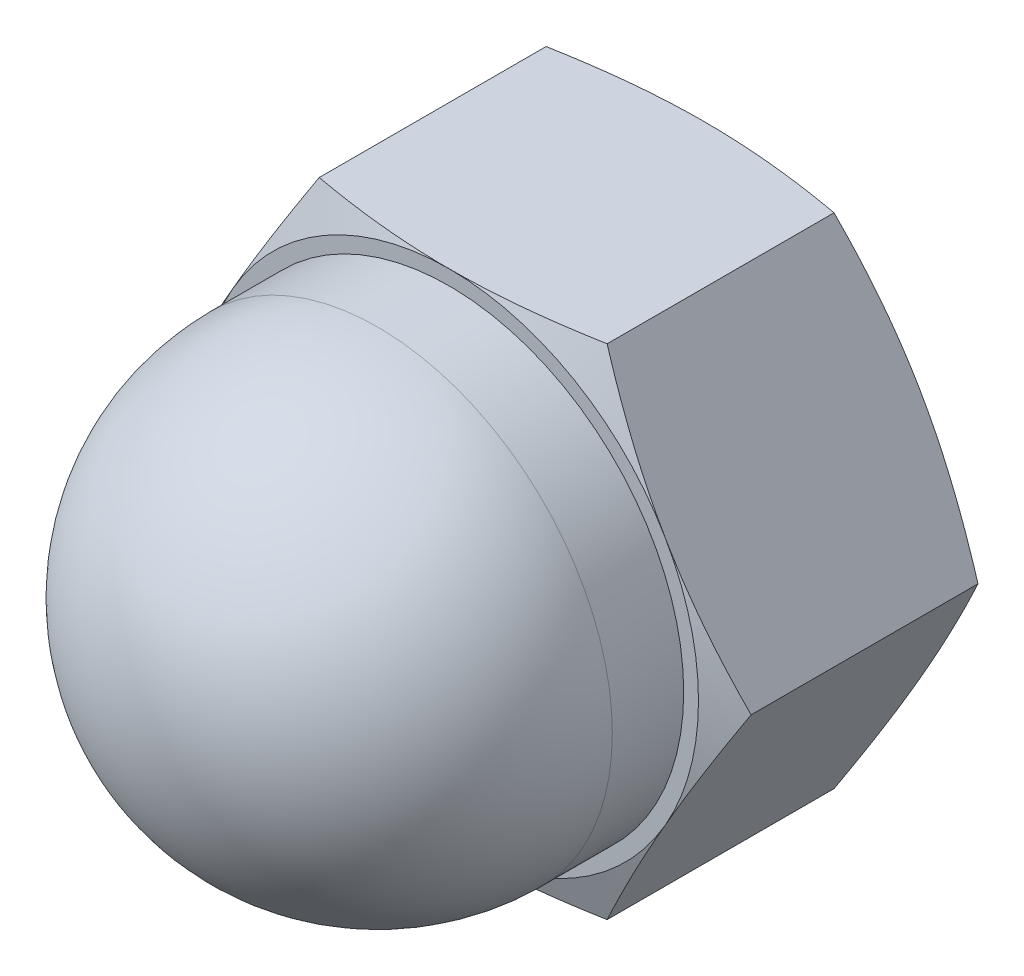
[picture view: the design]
ISO-10303-21;
HEADER;
FILE_DESCRIPTION(('STEP AP214'),'2;1');
FILE_NAME('part.step','',(''),(''),'','','');
FILE_SCHEMA(('AUTOMOTIVE_DESIGN { 1 0 10303 214 1 1 1 1 }'));
ENDSEC;
DATA;
#1=APPLICATION_CONTEXT('core data for automotive mechanical design processes');
#2=APPLICATION_PROTOCOL_DEFINITION('international standard','automotive_design',2000,#1);
#3=PRODUCT_CONTEXT('',#1,'mechanical');
#4=PRODUCT('Part','Part','',(#3));
#5=PRODUCT_RELATED_PRODUCT_CATEGORY('part','',(#4));
#6=PRODUCT_DEFINITION_FORMATION('','',#4);
#7=PRODUCT_DEFINITION_CONTEXT('part definition',#1,'design');
#8=PRODUCT_DEFINITION('design','',#6,#7);
#9=PRODUCT_DEFINITION_SHAPE('','',#8);
#10=(LENGTH_UNIT() NAMED_UNIT(*) SI_UNIT(.MILLI.,.METRE.));
#11=(NAMED_UNIT(*) PLANE_ANGLE_UNIT() SI_UNIT($,.RADIAN.));
#12=(NAMED_UNIT(*) SI_UNIT($,.STERADIAN.) SOLID_ANGLE_UNIT());
#13=UNCERTAINTY_MEASURE_WITH_UNIT(LENGTH_MEASURE(1.E-05),#10,'distance_accuracy_value','');
#14=(GEOMETRIC_REPRESENTATION_CONTEXT(3) GLOBAL_UNCERTAINTY_ASSIGNED_CONTEXT((#13)) GLOBAL_UNIT_ASSIGNED_CONTEXT((#10,
#11,#12)) REPRESENTATION_CONTEXT('',''));
#15=CARTESIAN_POINT('',(0.,0.,0.));
#16=DIRECTION('',(0.,0.,1.));
#17=DIRECTION('',(1.,0.,0.));
#18=AXIS2_PLACEMENT_3D('',#15,#16,#17);
#19=CARTESIAN_POINT('',(2.82324281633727,-4.89,0.));
#20=DIRECTION('',(0.,0.,-1.));
#21=DIRECTION('',(-1.,0.,0.));
#22=AXIS2_PLACEMENT_3D('',#19,#20,#21);
#23=PLANE('',#22);
#24=CARTESIAN_POINT('',(0.,0.,0.));
#25=DIRECTION('',(0.,0.,1.));
#26=DIRECTION('',(1.,0.,0.));
#27=AXIS2_PLACEMENT_3D('',#24,#25,#26);
#28=CIRCLE('',#27,4.6);
#29=CARTESIAN_POINT('',(4.6,0.,0.));
#30=VERTEX_POINT('',#29);
#31=EDGE_CURVE('E152',#30,#30,#28,.T.);
#32=ORIENTED_EDGE('',*,*,#31,.F.);
#33=EDGE_LOOP('',(#32));
#34=FACE_BOUND('',#33,.T.);
#35=CARTESIAN_POINT('',(0.,0.,0.));
#36=DIRECTION('',(0.,0.,-1.));
#37=DIRECTION('',(-1.,0.,0.));
#38=AXIS2_PLACEMENT_3D('',#35,#36,#37);
#39=CIRCLE('',#38,4.89);
#40=CARTESIAN_POINT('',(-4.2348642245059,2.445,0.));
#41=VERTEX_POINT('',#40);
#42=CARTESIAN_POINT('',(-4.2348642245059,-2.445,0.));
#43=VERTEX_POINT('',#42);
#44=EDGE_CURVE('E307',#41,#43,#39,.F.);
#45=ORIENTED_EDGE('',*,*,#44,.T.);
#46=CARTESIAN_POINT('',(0.,-4.89,0.));
#47=VERTEX_POINT('',#46);
#48=EDGE_CURVE('E62',#43,#47,#39,.F.);
#49=ORIENTED_EDGE('',*,*,#48,.T.);
#50=CARTESIAN_POINT('',(4.2348642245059,-2.445,0.));
#51=VERTEX_POINT('',#50);
#52=EDGE_CURVE('E313',#47,#51,#39,.F.);
#53=ORIENTED_EDGE('',*,*,#52,.T.);
#54=CARTESIAN_POINT('',(4.2348642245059,2.445,0.));
#55=VERTEX_POINT('',#54);
#56=EDGE_CURVE('E70',#51,#55,#39,.F.);
#57=ORIENTED_EDGE('',*,*,#56,.T.);
#58=CARTESIAN_POINT('',(0.,4.89,0.));
#59=VERTEX_POINT('',#58);
#60=EDGE_CURVE('E309',#55,#59,#39,.F.);
#61=ORIENTED_EDGE('',*,*,#60,.T.);
#62=CARTESIAN_POINT('',(0.,0.,0.));
#63=DIRECTION('',(0.,0.,-1.));
#64=DIRECTION('',(-1.,0.,0.));
#65=AXIS2_PLACEMENT_3D('',#62,#63,#64);
#66=CIRCLE('',#65,4.89);
#67=EDGE_CURVE('E160',#41,#59,#66,.T.);
#68=ORIENTED_EDGE('',*,*,#67,.F.);
#69=EDGE_LOOP('',(#45,#49,#53,#57,#61,#68));
#70=FACE_BOUND('',#69,.T.);
#71=ADVANCED_FACE('F47',(#34,#70),#23,.F.);
#72=CARTESIAN_POINT('',(2.82324281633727,-4.89,-5.));
#73=DIRECTION('',(0.866025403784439,-0.5,0.));
#74=DIRECTION('',(0.5,0.866025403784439,0.));
#75=AXIS2_PLACEMENT_3D('',#72,#73,#74);
#76=PLANE('',#75);
#77=CARTESIAN_POINT('',(2.82312734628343,-4.8902,-0.275380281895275));
#78=CARTESIAN_POINT('',(2.94005354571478,-4.68767788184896,-0.232806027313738));
#79=CARTESIAN_POINT('',(3.05736532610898,-4.48448791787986,-0.194077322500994));
#80=CARTESIAN_POINT('',(3.29275168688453,-4.07678678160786,-0.125940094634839));
#81=CARTESIAN_POINT('',(3.4108267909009,-3.87227470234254,-0.0965388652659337));
#82=CARTESIAN_POINT('',(3.64642938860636,-3.46419903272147,-0.04898319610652));
#83=CARTESIAN_POINT('',(3.7639515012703,-3.26064476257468,-0.0307250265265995));
#84=CARTESIAN_POINT('',(3.9992705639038,-2.85306019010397,-0.00623568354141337));
#85=CARTESIAN_POINT('',(4.11706739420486,-2.64903009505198,0.));
#86=CARTESIAN_POINT('',(4.35266105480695,-2.24096990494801,0.));
#87=CARTESIAN_POINT('',(4.470457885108,-2.03693980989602,-0.00623568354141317));
#88=CARTESIAN_POINT('',(4.7057769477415,-1.62935523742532,-0.0307250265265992));
#89=CARTESIAN_POINT('',(4.82329906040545,-1.42580096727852,-0.0489831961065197));
#90=CARTESIAN_POINT('',(5.05890165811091,-1.01772529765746,-0.0965388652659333));
#91=CARTESIAN_POINT('',(5.17697676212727,-0.813213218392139,-0.125940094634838));
#92=CARTESIAN_POINT('',(5.41236312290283,-0.40551208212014,-0.194077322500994));
#93=CARTESIAN_POINT('',(5.52967490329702,-0.202322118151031,-0.232806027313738));
#94=CARTESIAN_POINT('',(5.64660110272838,0.000200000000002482,-0.275380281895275));
#95=B_SPLINE_CURVE_WITH_KNOTS('',3,(#77,#78,#79,#80,#81,#82,#83,#84,#85,#86,#87,#88,#89,#90,#91,
#92,#93,#94),.UNSPECIFIED.,.F.,.F.,(4,2,2,2,2,2,2,2,4),(0.,0.713162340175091,1.42688097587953,
2.13385008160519,2.84055392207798,3.54725776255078,4.25422686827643,4.96794550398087,
5.68110784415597),.UNSPECIFIED.);
#96=CARTESIAN_POINT('',(2.82324281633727,-4.89,-0.275338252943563));
#97=VERTEX_POINT('',#96);
#98=EDGE_CURVE('E275',#97,#51,#95,.T.);
#99=ORIENTED_EDGE('',*,*,#98,.F.);
#100=DIRECTION('',(0.,0.,1.));
#101=VECTOR('',#100,1.);
#102=CARTESIAN_POINT('',(2.82324281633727,-4.89,-5.));
#103=LINE('',#102,#101);
#104=CARTESIAN_POINT('',(2.82324281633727,-4.89,-4.72466174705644));
#105=VERTEX_POINT('',#104);
#106=EDGE_CURVE('E278',#105,#97,#103,.T.);
#107=ORIENTED_EDGE('',*,*,#106,.F.);
#108=CARTESIAN_POINT('',(5.64660110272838,0.000200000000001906,-4.72461971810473));
#109=CARTESIAN_POINT('',(5.52967490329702,-0.202322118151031,-4.76719397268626));
#110=CARTESIAN_POINT('',(5.41236312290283,-0.405512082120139,-4.80592267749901));
#111=CARTESIAN_POINT('',(5.17697676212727,-0.813213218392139,-4.87405990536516));
#112=CARTESIAN_POINT('',(5.05890165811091,-1.01772529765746,-4.90346113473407));
#113=CARTESIAN_POINT('',(4.82329906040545,-1.42580096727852,-4.95101680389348));
#114=CARTESIAN_POINT('',(4.7057769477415,-1.62935523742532,-4.9692749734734));
#115=CARTESIAN_POINT('',(4.470457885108,-2.03693980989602,-4.99376431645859));
#116=CARTESIAN_POINT('',(4.35266105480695,-2.24096990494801,-5.));
#117=CARTESIAN_POINT('',(4.11706739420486,-2.64903009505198,-5.));
#118=CARTESIAN_POINT('',(3.99927056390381,-2.85306019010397,-4.99376431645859));
#119=CARTESIAN_POINT('',(3.76395150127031,-3.26064476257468,-4.9692749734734));
#120=CARTESIAN_POINT('',(3.64642938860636,-3.46419903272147,-4.95101680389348));
#121=CARTESIAN_POINT('',(3.4108267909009,-3.87227470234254,-4.90346113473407));
#122=CARTESIAN_POINT('',(3.29275168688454,-4.07678678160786,-4.87405990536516));
#123=CARTESIAN_POINT('',(3.05736532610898,-4.48448791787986,-4.80592267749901));
#124=CARTESIAN_POINT('',(2.94005354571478,-4.68767788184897,-4.76719397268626));
#125=CARTESIAN_POINT('',(2.82312734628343,-4.8902,-4.72461971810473));
#126=B_SPLINE_CURVE_WITH_KNOTS('',3,(#108,#109,#110,#111,#112,#113,#114,#115,#116,#117,#118,
#119,#120,#121,#122,#123,#124,#125),.UNSPECIFIED.,.F.,.F.,(4,2,2,2,2,2,2,2,4),(0.,
0.713162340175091,1.42688097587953,2.13385008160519,2.84055392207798,3.54725776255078,
4.25422686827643,4.96794550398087,5.68110784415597),.UNSPECIFIED.);
#127=CARTESIAN_POINT('',(4.2348642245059,-2.445,-5.));
#128=VERTEX_POINT('',#127);
#129=EDGE_CURVE('E255',#128,#105,#126,.T.);
#130=ORIENTED_EDGE('',*,*,#129,.F.);
#131=CARTESIAN_POINT('',(5.64648563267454,0.,-4.72466174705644));
#132=VERTEX_POINT('',#131);
#133=EDGE_CURVE('E261',#132,#128,#126,.T.);
#134=ORIENTED_EDGE('',*,*,#133,.F.);
#135=DIRECTION('',(0.,0.,1.));
#136=VECTOR('',#135,1.);
#137=CARTESIAN_POINT('',(5.64648563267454,0.,-5.));
#138=LINE('',#137,#136);
#139=CARTESIAN_POINT('',(5.64648563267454,0.,-0.275338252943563));
#140=VERTEX_POINT('',#139);
#141=EDGE_CURVE('E305',#132,#140,#138,.T.);
#142=ORIENTED_EDGE('',*,*,#141,.T.);
#143=EDGE_CURVE('E201',#51,#140,#95,.T.);
#144=ORIENTED_EDGE('',*,*,#143,.F.);
#145=EDGE_LOOP('',(#99,#107,#130,#134,#142,#144));
#146=FACE_BOUND('',#145,.T.);
#147=ADVANCED_FACE('F233',(#146),#76,.T.);
#148=CARTESIAN_POINT('',(-2.82324281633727,-4.89,-5.));
#149=DIRECTION('',(0.,-1.,0.));
#150=DIRECTION('',(0.,0.,-1.));
#151=AXIS2_PLACEMENT_3D('',#148,#149,#150);
#152=PLANE('',#151);
#153=CARTESIAN_POINT('',(-7.47495425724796,-4.89,-1.47129843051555));
#154=CARTESIAN_POINT('',(-7.25371297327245,-4.89,-1.40393054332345));
#155=CARTESIAN_POINT('',(-7.03222787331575,-4.89,-1.33734875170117));
#156=CARTESIAN_POINT('',(-6.5886459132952,-4.89,-1.20619222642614));
#157=CARTESIAN_POINT('',(-6.36654900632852,-4.89,-1.14161765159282));
#158=CARTESIAN_POINT('',(-5.92123916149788,-4.89,-1.01480300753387));
#159=CARTESIAN_POINT('',(-5.69802491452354,-4.89,-0.952567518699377));
#160=CARTESIAN_POINT('',(-5.25076608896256,-4.89,-0.831159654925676));
#161=CARTESIAN_POINT('',(-5.0267215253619,-4.89,-0.771987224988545));
#162=CARTESIAN_POINT('',(-4.58041494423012,-4.89,-0.658168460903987));
#163=CARTESIAN_POINT('',(-4.35816490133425,-4.89,-0.603475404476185));
#164=CARTESIAN_POINT('',(-3.91257162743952,-4.89,-0.498748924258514));
#165=CARTESIAN_POINT('',(-3.68922844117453,-4.89,-0.448715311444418));
#166=CARTESIAN_POINT('',(-3.24137981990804,-4.89,-0.354469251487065));
#167=CARTESIAN_POINT('',(-3.01687477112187,-4.89,-0.310254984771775));
#168=CARTESIAN_POINT('',(-2.56656126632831,-4.89,-0.228995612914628));
#169=CARTESIAN_POINT('',(-2.34075285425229,-4.89,-0.191950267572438));
#170=CARTESIAN_POINT('',(-1.91325953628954,-4.89,-0.130201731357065));
#171=CARTESIAN_POINT('',(-1.71170849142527,-4.89,-0.104580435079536));
#172=CARTESIAN_POINT('',(-1.30775414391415,-4.89,-0.0612096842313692));
#173=CARTESIAN_POINT('',(-1.10535086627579,-4.89,-0.043460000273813));
#174=CARTESIAN_POINT('',(-0.700102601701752,-4.89,-0.0166872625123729));
#175=CARTESIAN_POINT('',(-0.497258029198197,-4.89,-0.0076580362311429));
#176=CARTESIAN_POINT('',(-0.0913659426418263,-4.89,0.00121663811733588));
#177=CARTESIAN_POINT('',(0.111681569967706,-4.89,0.00106215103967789));
#178=CARTESIAN_POINT('',(0.518587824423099,-4.89,-0.00844625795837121));
#179=CARTESIAN_POINT('',(0.722445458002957,-4.89,-0.0178468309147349));
#180=CARTESIAN_POINT('',(1.12956194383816,-4.89,-0.0454147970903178));
#181=CARTESIAN_POINT('',(1.33282078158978,-4.89,-0.0635824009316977));
#182=CARTESIAN_POINT('',(1.73863931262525,-4.89,-0.107834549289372));
#183=CARTESIAN_POINT('',(1.94119825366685,-4.89,-0.133925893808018));
#184=CARTESIAN_POINT('',(2.34530277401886,-4.89,-0.192967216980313));
#185=CARTESIAN_POINT('',(2.54684834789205,-4.89,-0.225917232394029));
#186=CARTESIAN_POINT('',(2.95953215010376,-4.89,-0.299499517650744));
#187=CARTESIAN_POINT('',(3.17061386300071,-4.89,-0.340445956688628));
#188=CARTESIAN_POINT('',(3.59169320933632,-4.89,-0.427609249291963));
#189=CARTESIAN_POINT('',(3.80169075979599,-4.89,-0.473826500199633));
#190=CARTESIAN_POINT('',(4.22074597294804,-4.89,-0.570557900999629));
#191=CARTESIAN_POINT('',(4.42980337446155,-4.89,-0.621073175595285));
#192=CARTESIAN_POINT('',(4.84704782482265,-4.89,-0.725589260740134));
#193=CARTESIAN_POINT('',(5.05523484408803,-4.89,-0.779590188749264));
#194=CARTESIAN_POINT('',(5.67918655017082,-4.89,-0.945945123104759));
#195=CARTESIAN_POINT('',(6.09382208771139,-4.89,-1.06252765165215));
#196=CARTESIAN_POINT('',(6.92081542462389,-4.89,-1.30317591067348));
#197=CARTESIAN_POINT('',(7.33317357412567,-4.89,-1.42724045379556));
#198=CARTESIAN_POINT('',(8.15174363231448,-4.89,-1.67916430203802));
#199=CARTESIAN_POINT('',(8.55797314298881,-4.89,-1.80696660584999));
#200=CARTESIAN_POINT('',(9.3692896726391,-4.89,-2.06620027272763));
#201=CARTESIAN_POINT('',(9.77437663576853,-4.89,-2.197631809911));
#202=CARTESIAN_POINT('',(10.5821449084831,-4.89,-2.46263754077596));
#203=CARTESIAN_POINT('',(10.9848295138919,-4.89,-2.59620171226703));
#204=CARTESIAN_POINT('',(11.7894926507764,-4.89,-2.86533263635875));
#205=CARTESIAN_POINT('',(12.1914712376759,-4.89,-3.0008992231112));
#206=CARTESIAN_POINT('',(12.5932087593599,-4.89,-3.13716622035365));
#207=B_SPLINE_CURVE_WITH_KNOTS('',3,(#153,#154,#155,#156,#157,#158,#159,#160,#161,#162,#163,
#164,#165,#166,#167,#168,#169,#170,#171,#172,#173,#174,#175,#176,#177,#178,#179,#180,#181,#182,
#183,#184,#185,#186,#187,#188,#189,#190,#191,#192,#193,#194,#195,#196,#197,#198,#199,#200,#201,
#202,#203,#204,#205,#206),.UNSPECIFIED.,.F.,.F.,(4,2,2,2,2,2,2,2,2,2,2,2,2,2,2,2,2,2,2,2,2,2,2,
2,2,2,4),(0.,0.693817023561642,1.38768880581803,2.08285517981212,2.77800906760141,
3.46461177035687,4.15118660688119,4.83754625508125,5.52388290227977,6.1332681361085,
6.74263561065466,7.35157144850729,7.9605029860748,8.57252272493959,9.18455716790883,
9.79711833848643,10.4096827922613,11.054649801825,11.6996654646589,12.3448504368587,
12.9900571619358,14.2820728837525,15.5738841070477,16.8514365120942,18.1290503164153,
19.4018164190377,20.6744776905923),.UNSPECIFIED.);
#208=CARTESIAN_POINT('',(-2.82324281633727,-4.89,-0.275338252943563));
#209=VERTEX_POINT('',#208);
#210=EDGE_CURVE('E220',#209,#47,#207,.T.);
#211=ORIENTED_EDGE('',*,*,#210,.F.);
#212=DIRECTION('',(0.,0.,1.));
#213=VECTOR('',#212,1.);
#214=CARTESIAN_POINT('',(-2.82324281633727,-4.89,-5.));
#215=LINE('',#214,#213);
#216=CARTESIAN_POINT('',(-2.82324281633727,-4.89,-4.72466174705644));
#217=VERTEX_POINT('',#216);
#218=EDGE_CURVE('E288',#217,#209,#215,.T.);
#219=ORIENTED_EDGE('',*,*,#218,.F.);
#220=CARTESIAN_POINT('',(-7.47495425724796,-4.89,-3.52870156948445));
#221=CARTESIAN_POINT('',(-7.25371297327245,-4.89,-3.59606945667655));
#222=CARTESIAN_POINT('',(-7.03222787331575,-4.89,-3.66265124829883));
#223=CARTESIAN_POINT('',(-6.5886459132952,-4.89,-3.79380777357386));
#224=CARTESIAN_POINT('',(-6.36654900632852,-4.89,-3.85838234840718));
#225=CARTESIAN_POINT('',(-5.92123916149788,-4.89,-3.98519699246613));
#226=CARTESIAN_POINT('',(-5.69802491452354,-4.89,-4.04743248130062));
#227=CARTESIAN_POINT('',(-5.25076608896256,-4.89,-4.16884034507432));
#228=CARTESIAN_POINT('',(-5.0267215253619,-4.89,-4.22801277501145));
#229=CARTESIAN_POINT('',(-4.58041494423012,-4.89,-4.34183153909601));
#230=CARTESIAN_POINT('',(-4.35816490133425,-4.89,-4.39652459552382));
#231=CARTESIAN_POINT('',(-3.91257162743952,-4.89,-4.50125107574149));
#232=CARTESIAN_POINT('',(-3.68922844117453,-4.89,-4.55128468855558));
#233=CARTESIAN_POINT('',(-3.24137981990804,-4.89,-4.64553074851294));
#234=CARTESIAN_POINT('',(-3.01687477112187,-4.89,-4.68974501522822));
#235=CARTESIAN_POINT('',(-2.56656126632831,-4.89,-4.77100438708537));
#236=CARTESIAN_POINT('',(-2.34075285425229,-4.89,-4.80804973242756));
#237=CARTESIAN_POINT('',(-1.91325953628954,-4.89,-4.86979826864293));
#238=CARTESIAN_POINT('',(-1.71170849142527,-4.89,-4.89541956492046));
#239=CARTESIAN_POINT('',(-1.30775414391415,-4.89,-4.93879031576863));
#240=CARTESIAN_POINT('',(-1.10535086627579,-4.89,-4.95653999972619));
#241=CARTESIAN_POINT('',(-0.700102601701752,-4.89,-4.98331273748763));
#242=CARTESIAN_POINT('',(-0.497258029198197,-4.89,-4.99234196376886));
#243=CARTESIAN_POINT('',(-0.0913659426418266,-4.89,-5.00121663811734));
#244=CARTESIAN_POINT('',(0.111681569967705,-4.89,-5.00106215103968));
#245=CARTESIAN_POINT('',(0.518587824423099,-4.89,-4.99155374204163));
#246=CARTESIAN_POINT('',(0.722445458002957,-4.89,-4.98215316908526));
#247=CARTESIAN_POINT('',(1.12956194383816,-4.89,-4.95458520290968));
#248=CARTESIAN_POINT('',(1.33282078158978,-4.89,-4.9364175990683));
#249=CARTESIAN_POINT('',(1.73863931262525,-4.89,-4.89216545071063));
#250=CARTESIAN_POINT('',(1.94119825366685,-4.89,-4.86607410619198));
#251=CARTESIAN_POINT('',(2.34530277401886,-4.89,-4.80703278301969));
#252=CARTESIAN_POINT('',(2.54684834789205,-4.89,-4.77408276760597));
#253=CARTESIAN_POINT('',(2.95953215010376,-4.89,-4.70050048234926));
#254=CARTESIAN_POINT('',(3.17061386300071,-4.89,-4.65955404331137));
#255=CARTESIAN_POINT('',(3.59169320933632,-4.89,-4.57239075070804));
#256=CARTESIAN_POINT('',(3.80169075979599,-4.89,-4.52617349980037));
#257=CARTESIAN_POINT('',(4.22074597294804,-4.89,-4.42944209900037));
#258=CARTESIAN_POINT('',(4.42980337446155,-4.89,-4.37892682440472));
#259=CARTESIAN_POINT('',(4.84704782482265,-4.89,-4.27441073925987));
#260=CARTESIAN_POINT('',(5.05523484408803,-4.89,-4.22040981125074));
#261=CARTESIAN_POINT('',(5.67918655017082,-4.89,-4.05405487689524));
#262=CARTESIAN_POINT('',(6.09382208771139,-4.89,-3.93747234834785));
#263=CARTESIAN_POINT('',(6.92081542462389,-4.89,-3.69682408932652));
#264=CARTESIAN_POINT('',(7.33317357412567,-4.89,-3.57275954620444));
#265=CARTESIAN_POINT('',(8.15174363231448,-4.89,-3.32083569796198));
#266=CARTESIAN_POINT('',(8.55797314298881,-4.89,-3.19303339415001));
#267=CARTESIAN_POINT('',(9.3692896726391,-4.89,-2.93379972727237));
#268=CARTESIAN_POINT('',(9.77437663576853,-4.89,-2.802368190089));
#269=CARTESIAN_POINT('',(10.5821449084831,-4.89,-2.53736245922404));
#270=CARTESIAN_POINT('',(10.9848295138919,-4.89,-2.40379828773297));
#271=CARTESIAN_POINT('',(11.7894926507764,-4.89,-2.13466736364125));
#272=CARTESIAN_POINT('',(12.1914712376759,-4.89,-1.9991007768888));
#273=CARTESIAN_POINT('',(12.5932087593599,-4.89,-1.86283377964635));
#274=B_SPLINE_CURVE_WITH_KNOTS('',3,(#220,#221,#222,#223,#224,#225,#226,#227,#228,#229,#230,
#231,#232,#233,#234,#235,#236,#237,#238,#239,#240,#241,#242,#243,#244,#245,#246,#247,#248,#249,
#250,#251,#252,#253,#254,#255,#256,#257,#258,#259,#260,#261,#262,#263,#264,#265,#266,#267,#268,
#269,#270,#271,#272,#273),.UNSPECIFIED.,.F.,.F.,(4,2,2,2,2,2,2,2,2,2,2,2,2,2,2,2,2,2,2,2,2,2,2,
2,2,2,4),(0.,0.693817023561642,1.38768880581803,2.08285517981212,2.77800906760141,
3.46461177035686,4.15118660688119,4.83754625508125,5.52388290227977,6.1332681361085,
6.74263561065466,7.35157144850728,7.9605029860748,8.57252272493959,9.18455716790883,
9.79711833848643,10.4096827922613,11.054649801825,11.6996654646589,12.3448504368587,
12.9900571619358,14.2820728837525,15.5738841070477,16.8514365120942,18.1290503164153,
19.4018164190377,20.6744776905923),.UNSPECIFIED.);
#275=CARTESIAN_POINT('',(0.,-4.89,-5.));
#276=VERTEX_POINT('',#275);
#277=EDGE_CURVE('E240',#276,#217,#274,.F.);
#278=ORIENTED_EDGE('',*,*,#277,.F.);
#279=EDGE_CURVE('E247',#105,#276,#274,.F.);
#280=ORIENTED_EDGE('',*,*,#279,.F.);
#281=ORIENTED_EDGE('',*,*,#106,.T.);
#282=EDGE_CURVE('E214',#47,#97,#207,.T.);
#283=ORIENTED_EDGE('',*,*,#282,.F.);
#284=EDGE_LOOP('',(#211,#219,#278,#280,#281,#283));
#285=FACE_BOUND('',#284,.T.);
#286=ADVANCED_FACE('F228',(#285),#152,.T.);
#287=CARTESIAN_POINT('',(-5.64648563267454,0.,-5.));
#288=DIRECTION('',(-0.866025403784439,-0.5,0.));
#289=DIRECTION('',(0.5,-0.866025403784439,0.));
#290=AXIS2_PLACEMENT_3D('',#287,#288,#289);
#291=PLANE('',#290);
#292=CARTESIAN_POINT('',(-5.64660110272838,0.000199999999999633,-0.275380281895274));
#293=CARTESIAN_POINT('',(-5.52967490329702,-0.202322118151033,-0.232806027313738));
#294=CARTESIAN_POINT('',(-5.41236312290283,-0.405512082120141,-0.194077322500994));
#295=CARTESIAN_POINT('',(-5.17697676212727,-0.813213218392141,-0.125940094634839));
#296=CARTESIAN_POINT('',(-5.05890165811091,-1.01772529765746,-0.0965388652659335));
#297=CARTESIAN_POINT('',(-4.82329906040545,-1.42580096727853,-0.0489831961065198));
#298=CARTESIAN_POINT('',(-4.7057769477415,-1.62935523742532,-0.0307250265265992));
#299=CARTESIAN_POINT('',(-4.470457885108,-2.03693980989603,-0.00623568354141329));
#300=CARTESIAN_POINT('',(-4.35266105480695,-2.24096990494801,0.));
#301=CARTESIAN_POINT('',(-4.11706739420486,-2.64903009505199,0.));
#302=CARTESIAN_POINT('',(-3.9992705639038,-2.85306019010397,-0.0062356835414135));
#303=CARTESIAN_POINT('',(-3.7639515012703,-3.26064476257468,-0.0307250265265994));
#304=CARTESIAN_POINT('',(-3.64642938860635,-3.46419903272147,-0.0489831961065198));
#305=CARTESIAN_POINT('',(-3.41082679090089,-3.87227470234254,-0.0965388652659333));
#306=CARTESIAN_POINT('',(-3.29275168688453,-4.07678678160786,-0.125940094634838));
#307=CARTESIAN_POINT('',(-3.05736532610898,-4.48448791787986,-0.194077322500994));
#308=CARTESIAN_POINT('',(-2.94005354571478,-4.68767788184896,-0.232806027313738));
#309=CARTESIAN_POINT('',(-2.82312734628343,-4.8902,-0.275380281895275));
#310=B_SPLINE_CURVE_WITH_KNOTS('',3,(#292,#293,#294,#295,#296,#297,#298,#299,#300,#301,#302,
#303,#304,#305,#306,#307,#308,#309),.UNSPECIFIED.,.F.,.F.,(4,2,2,2,2,2,2,2,4),(0.,
0.713162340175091,1.42688097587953,2.13385008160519,2.84055392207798,3.54725776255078,
4.25422686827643,4.96794550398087,5.68110784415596),.UNSPECIFIED.);
#311=CARTESIAN_POINT('',(-5.64648563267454,0.,-0.275338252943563));
#312=VERTEX_POINT('',#311);
#313=EDGE_CURVE('E373',#312,#43,#310,.T.);
#314=ORIENTED_EDGE('',*,*,#313,.F.);
#315=DIRECTION('',(0.,0.,1.));
#316=VECTOR('',#315,1.);
#317=CARTESIAN_POINT('',(-5.64648563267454,0.,-5.));
#318=LINE('',#317,#316);
#319=CARTESIAN_POINT('',(-5.64648563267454,0.,-4.72466174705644));
#320=VERTEX_POINT('',#319);
#321=EDGE_CURVE('E294',#320,#312,#318,.T.);
#322=ORIENTED_EDGE('',*,*,#321,.F.);
#323=CARTESIAN_POINT('',(-2.82312734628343,-4.8902,-4.72461971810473));
#324=CARTESIAN_POINT('',(-2.94005354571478,-4.68767788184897,-4.76719397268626));
#325=CARTESIAN_POINT('',(-3.05736532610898,-4.48448791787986,-4.80592267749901));
#326=CARTESIAN_POINT('',(-3.29275168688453,-4.07678678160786,-4.87405990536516));
#327=CARTESIAN_POINT('',(-3.41082679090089,-3.87227470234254,-4.90346113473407));
#328=CARTESIAN_POINT('',(-3.64642938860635,-3.46419903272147,-4.95101680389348));
#329=CARTESIAN_POINT('',(-3.7639515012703,-3.26064476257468,-4.9692749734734));
#330=CARTESIAN_POINT('',(-3.9992705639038,-2.85306019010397,-4.99376431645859));
#331=CARTESIAN_POINT('',(-4.11706739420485,-2.64903009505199,-5.));
#332=CARTESIAN_POINT('',(-4.35266105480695,-2.24096990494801,-5.));
#333=CARTESIAN_POINT('',(-4.470457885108,-2.03693980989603,-4.99376431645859));
#334=CARTESIAN_POINT('',(-4.7057769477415,-1.62935523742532,-4.9692749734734));
#335=CARTESIAN_POINT('',(-4.82329906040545,-1.42580096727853,-4.95101680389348));
#336=CARTESIAN_POINT('',(-5.05890165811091,-1.01772529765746,-4.90346113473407));
#337=CARTESIAN_POINT('',(-5.17697676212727,-0.813213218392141,-4.87405990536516));
#338=CARTESIAN_POINT('',(-5.41236312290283,-0.405512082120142,-4.80592267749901));
#339=CARTESIAN_POINT('',(-5.52967490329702,-0.202322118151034,-4.76719397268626));
#340=CARTESIAN_POINT('',(-5.64660110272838,0.000199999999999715,-4.72461971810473));
#341=B_SPLINE_CURVE_WITH_KNOTS('',3,(#323,#324,#325,#326,#327,#328,#329,#330,#331,#332,#333,
#334,#335,#336,#337,#338,#339,#340),.UNSPECIFIED.,.F.,.F.,(4,2,2,2,2,2,2,2,4),(0.,
0.713162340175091,1.42688097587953,2.13385008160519,2.84055392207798,3.54725776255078,
4.25422686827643,4.96794550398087,5.68110784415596),.UNSPECIFIED.);
#342=CARTESIAN_POINT('',(-4.2348642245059,-2.445,-5.));
#343=VERTEX_POINT('',#342);
#344=EDGE_CURVE('E249',#343,#320,#341,.T.);
#345=ORIENTED_EDGE('',*,*,#344,.F.);
#346=EDGE_CURVE('E248',#217,#343,#341,.T.);
#347=ORIENTED_EDGE('',*,*,#346,.F.);
#348=ORIENTED_EDGE('',*,*,#218,.T.);
#349=EDGE_CURVE('E221',#43,#209,#310,.T.);
#350=ORIENTED_EDGE('',*,*,#349,.F.);
#351=EDGE_LOOP('',(#314,#322,#345,#347,#348,#350));
#352=FACE_BOUND('',#351,.T.);
#353=ADVANCED_FACE('F232',(#352),#291,.T.);
#354=CARTESIAN_POINT('',(-2.82324281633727,4.89,-5.));
#355=DIRECTION('',(-0.866025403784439,0.5,0.));
#356=DIRECTION('',(-0.5,-0.866025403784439,0.));
#357=AXIS2_PLACEMENT_3D('',#354,#355,#356);
#358=PLANE('',#357);
#359=CARTESIAN_POINT('',(-2.82312734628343,4.8902,-0.275380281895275));
#360=CARTESIAN_POINT('',(-2.94005354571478,4.68767788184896,-0.232806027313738));
#361=CARTESIAN_POINT('',(-3.05736532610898,4.48448791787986,-0.194077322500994));
#362=CARTESIAN_POINT('',(-3.29275168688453,4.07678678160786,-0.125940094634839));
#363=CARTESIAN_POINT('',(-3.4108267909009,3.87227470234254,-0.0965388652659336));
#364=CARTESIAN_POINT('',(-3.64642938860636,3.46419903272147,-0.04898319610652));
#365=CARTESIAN_POINT('',(-3.76395150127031,3.26064476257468,-0.0307250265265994));
#366=CARTESIAN_POINT('',(-3.99927056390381,2.85306019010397,-0.00623568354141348));
#367=CARTESIAN_POINT('',(-4.11706739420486,2.64903009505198,0.));
#368=CARTESIAN_POINT('',(-4.35266105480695,2.24096990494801,0.));
#369=CARTESIAN_POINT('',(-4.470457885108,2.03693980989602,-0.00623568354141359));
#370=CARTESIAN_POINT('',(-4.7057769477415,1.62935523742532,-0.0307250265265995));
#371=CARTESIAN_POINT('',(-4.82329906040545,1.42580096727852,-0.04898319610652));
#372=CARTESIAN_POINT('',(-5.05890165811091,1.01772529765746,-0.0965388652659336));
#373=CARTESIAN_POINT('',(-5.17697676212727,0.81321321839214,-0.125940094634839));
#374=CARTESIAN_POINT('',(-5.41236312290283,0.405512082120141,-0.194077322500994));
#375=CARTESIAN_POINT('',(-5.52967490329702,0.202322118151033,-0.232806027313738));
#376=CARTESIAN_POINT('',(-5.64660110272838,-0.000200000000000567,-0.275380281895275));
#377=B_SPLINE_CURVE_WITH_KNOTS('',3,(#359,#360,#361,#362,#363,#364,#365,#366,#367,#368,#369,
#370,#371,#372,#373,#374,#375,#376),.UNSPECIFIED.,.F.,.F.,(4,2,2,2,2,2,2,2,4),(0.,
0.713162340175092,1.42688097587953,2.13385008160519,2.84055392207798,3.54725776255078,
4.25422686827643,4.96794550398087,5.68110784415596),.UNSPECIFIED.);
#378=CARTESIAN_POINT('',(-2.82324281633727,4.89,-0.275338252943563));
#379=VERTEX_POINT('',#378);
#380=EDGE_CURVE('E207',#379,#41,#377,.T.);
#381=ORIENTED_EDGE('',*,*,#380,.F.);
#382=DIRECTION('',(0.,0.,1.));
#383=VECTOR('',#382,1.);
#384=CARTESIAN_POINT('',(-2.82324281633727,4.89,-5.));
#385=LINE('',#384,#383);
#386=CARTESIAN_POINT('',(-2.82324281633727,4.89,-4.72466174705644));
#387=VERTEX_POINT('',#386);
#388=EDGE_CURVE('E299',#387,#379,#385,.T.);
#389=ORIENTED_EDGE('',*,*,#388,.F.);
#390=CARTESIAN_POINT('',(-5.64660110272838,-0.000200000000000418,-4.72461971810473));
#391=CARTESIAN_POINT('',(-5.52967490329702,0.202322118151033,-4.76719397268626));
#392=CARTESIAN_POINT('',(-5.41236312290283,0.405512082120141,-4.80592267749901));
#393=CARTESIAN_POINT('',(-5.17697676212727,0.81321321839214,-4.87405990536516));
#394=CARTESIAN_POINT('',(-5.05890165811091,1.01772529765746,-4.90346113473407));
#395=CARTESIAN_POINT('',(-4.82329906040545,1.42580096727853,-4.95101680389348));
#396=CARTESIAN_POINT('',(-4.7057769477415,1.62935523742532,-4.9692749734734));
#397=CARTESIAN_POINT('',(-4.470457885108,2.03693980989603,-4.99376431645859));
#398=CARTESIAN_POINT('',(-4.35266105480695,2.24096990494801,-5.));
#399=CARTESIAN_POINT('',(-4.11706739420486,2.64903009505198,-5.));
#400=CARTESIAN_POINT('',(-3.99927056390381,2.85306019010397,-4.99376431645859));
#401=CARTESIAN_POINT('',(-3.76395150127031,3.26064476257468,-4.9692749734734));
#402=CARTESIAN_POINT('',(-3.64642938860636,3.46419903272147,-4.95101680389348));
#403=CARTESIAN_POINT('',(-3.4108267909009,3.87227470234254,-4.90346113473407));
#404=CARTESIAN_POINT('',(-3.29275168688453,4.07678678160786,-4.87405990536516));
#405=CARTESIAN_POINT('',(-3.05736532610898,4.48448791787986,-4.80592267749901));
#406=CARTESIAN_POINT('',(-2.94005354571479,4.68767788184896,-4.76719397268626));
#407=CARTESIAN_POINT('',(-2.82312734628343,4.8902,-4.72461971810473));
#408=B_SPLINE_CURVE_WITH_KNOTS('',3,(#390,#391,#392,#393,#394,#395,#396,#397,#398,#399,#400,
#401,#402,#403,#404,#405,#406,#407),.UNSPECIFIED.,.F.,.F.,(4,2,2,2,2,2,2,2,4),(0.,
0.713162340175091,1.42688097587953,2.13385008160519,2.84055392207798,3.54725776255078,
4.25422686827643,4.96794550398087,5.68110784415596),.UNSPECIFIED.);
#409=CARTESIAN_POINT('',(-4.2348642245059,2.445,-5.));
#410=VERTEX_POINT('',#409);
#411=EDGE_CURVE('E342',#410,#387,#408,.T.);
#412=ORIENTED_EDGE('',*,*,#411,.F.);
#413=EDGE_CURVE('E415',#320,#410,#408,.T.);
#414=ORIENTED_EDGE('',*,*,#413,.F.);
#415=ORIENTED_EDGE('',*,*,#321,.T.);
#416=EDGE_CURVE('E326',#41,#312,#377,.T.);
#417=ORIENTED_EDGE('',*,*,#416,.F.);
#418=EDGE_LOOP('',(#381,#389,#412,#414,#415,#417));
#419=FACE_BOUND('',#418,.T.);
#420=ADVANCED_FACE('F359',(#419),#358,.T.);
#421=CARTESIAN_POINT('',(2.82324281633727,4.89,-5.));
#422=DIRECTION('',(0.,1.,0.));
#423=DIRECTION('',(-1.,0.,0.));
#424=AXIS2_PLACEMENT_3D('',#421,#422,#423);
#425=PLANE('',#424);
#426=CARTESIAN_POINT('',(-7.47495425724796,4.89,-1.47129843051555));
#427=CARTESIAN_POINT('',(-7.25371297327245,4.89,-1.40393054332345));
#428=CARTESIAN_POINT('',(-7.03222787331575,4.89,-1.33734875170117));
#429=CARTESIAN_POINT('',(-6.5886459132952,4.89,-1.20619222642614));
#430=CARTESIAN_POINT('',(-6.36654900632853,4.89,-1.14161765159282));
#431=CARTESIAN_POINT('',(-5.92123916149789,4.89,-1.01480300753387));
#432=CARTESIAN_POINT('',(-5.69802491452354,4.89,-0.952567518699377));
#433=CARTESIAN_POINT('',(-5.25076608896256,4.89,-0.831159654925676));
#434=CARTESIAN_POINT('',(-5.0267215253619,4.89,-0.771987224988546));
#435=CARTESIAN_POINT('',(-4.58041494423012,4.89,-0.658168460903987));
#436=CARTESIAN_POINT('',(-4.35816490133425,4.89,-0.603475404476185));
#437=CARTESIAN_POINT('',(-3.91257162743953,4.89,-0.498748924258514));
#438=CARTESIAN_POINT('',(-3.68922844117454,4.89,-0.448715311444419));
#439=CARTESIAN_POINT('',(-3.24137981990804,4.89,-0.354469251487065));
#440=CARTESIAN_POINT('',(-3.01687477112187,4.89,-0.310254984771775));
#441=CARTESIAN_POINT('',(-2.56656126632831,4.89,-0.228995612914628));
#442=CARTESIAN_POINT('',(-2.34075285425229,4.89,-0.191950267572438));
#443=CARTESIAN_POINT('',(-1.91325953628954,4.89,-0.130201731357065));
#444=CARTESIAN_POINT('',(-1.71170849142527,4.89,-0.104580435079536));
#445=CARTESIAN_POINT('',(-1.30775414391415,4.89,-0.061209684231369));
#446=CARTESIAN_POINT('',(-1.10535086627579,4.89,-0.0434600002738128));
#447=CARTESIAN_POINT('',(-0.700102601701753,4.89,-0.0166872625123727));
#448=CARTESIAN_POINT('',(-0.497258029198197,4.89,-0.00765803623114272));
#449=CARTESIAN_POINT('',(-0.091365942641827,4.89,0.00121663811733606));
#450=CARTESIAN_POINT('',(0.111681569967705,4.89,0.00106215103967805));
#451=CARTESIAN_POINT('',(0.518587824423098,4.89,-0.00844625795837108));
#452=CARTESIAN_POINT('',(0.722445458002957,4.89,-0.0178468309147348));
#453=CARTESIAN_POINT('',(1.12956194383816,4.89,-0.0454147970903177));
#454=CARTESIAN_POINT('',(1.33282078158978,4.89,-0.0635824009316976));
#455=CARTESIAN_POINT('',(1.73863931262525,4.89,-0.107834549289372));
#456=CARTESIAN_POINT('',(1.94119825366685,4.89,-0.133925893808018));
#457=CARTESIAN_POINT('',(2.34530277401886,4.89,-0.192967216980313));
#458=CARTESIAN_POINT('',(2.54684834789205,4.89,-0.225917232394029));
#459=CARTESIAN_POINT('',(2.95953215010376,4.89,-0.299499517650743));
#460=CARTESIAN_POINT('',(3.1706138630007,4.89,-0.340445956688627));
#461=CARTESIAN_POINT('',(3.59169320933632,4.89,-0.427609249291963));
#462=CARTESIAN_POINT('',(3.80169075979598,4.89,-0.473826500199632));
#463=CARTESIAN_POINT('',(4.22074597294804,4.89,-0.570557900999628));
#464=CARTESIAN_POINT('',(4.42980337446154,4.89,-0.621073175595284));
#465=CARTESIAN_POINT('',(4.84704782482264,4.89,-0.725589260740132));
#466=CARTESIAN_POINT('',(5.05523484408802,4.89,-0.779590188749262));
#467=CARTESIAN_POINT('',(5.67918655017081,4.89,-0.945945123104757));
#468=CARTESIAN_POINT('',(6.09382208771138,4.89,-1.06252765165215));
#469=CARTESIAN_POINT('',(6.92081542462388,4.89,-1.30317591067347));
#470=CARTESIAN_POINT('',(7.33317357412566,4.89,-1.42724045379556));
#471=CARTESIAN_POINT('',(8.15174363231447,4.89,-1.67916430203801));
#472=CARTESIAN_POINT('',(8.55797314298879,4.89,-1.80696660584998));
#473=CARTESIAN_POINT('',(9.36928967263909,4.89,-2.06620027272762));
#474=CARTESIAN_POINT('',(9.77437663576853,4.89,-2.19763180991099));
#475=CARTESIAN_POINT('',(10.5821449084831,4.89,-2.46263754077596));
#476=CARTESIAN_POINT('',(10.9848295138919,4.89,-2.59620171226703));
#477=CARTESIAN_POINT('',(11.7894926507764,4.89,-2.86533263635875));
#478=CARTESIAN_POINT('',(12.1914712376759,4.89,-3.0008992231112));
#479=CARTESIAN_POINT('',(12.5932087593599,4.89,-3.13716622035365));
#480=B_SPLINE_CURVE_WITH_KNOTS('',3,(#426,#427,#428,#429,#430,#431,#432,#433,#434,#435,#436,
#437,#438,#439,#440,#441,#442,#443,#444,#445,#446,#447,#448,#449,#450,#451,#452,#453,#454,#455,
#456,#457,#458,#459,#460,#461,#462,#463,#464,#465,#466,#467,#468,#469,#470,#471,#472,#473,#474,
#475,#476,#477,#478,#479),.UNSPECIFIED.,.F.,.F.,(4,2,2,2,2,2,2,2,2,2,2,2,2,2,2,2,2,2,2,2,2,2,2,
2,2,2,4),(0.,0.693817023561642,1.38768880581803,2.08285517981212,2.7780090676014,
3.46461177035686,4.15118660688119,4.83754625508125,5.52388290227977,6.1332681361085,
6.74263561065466,7.35157144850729,7.9605029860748,8.57252272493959,9.18455716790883,
9.79711833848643,10.4096827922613,11.0546498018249,11.6996654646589,12.3448504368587,
12.9900571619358,14.2820728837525,15.5738841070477,16.8514365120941,18.1290503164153,
19.4018164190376,20.6744776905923),.UNSPECIFIED.);
#481=CARTESIAN_POINT('',(2.82324281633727,4.89,-0.275338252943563));
#482=VERTEX_POINT('',#481);
#483=EDGE_CURVE('E172',#482,#59,#480,.F.);
#484=ORIENTED_EDGE('',*,*,#483,.F.);
#485=DIRECTION('',(0.,0.,1.));
#486=VECTOR('',#485,1.);
#487=CARTESIAN_POINT('',(2.82324281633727,4.89,-5.));
#488=LINE('',#487,#486);
#489=CARTESIAN_POINT('',(2.82324281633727,4.89,-4.72466174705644));
#490=VERTEX_POINT('',#489);
#491=EDGE_CURVE('E302',#490,#482,#488,.T.);
#492=ORIENTED_EDGE('',*,*,#491,.F.);
#493=CARTESIAN_POINT('',(-7.47495425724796,4.89,-3.52870156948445));
#494=CARTESIAN_POINT('',(-7.25371297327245,4.89,-3.59606945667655));
#495=CARTESIAN_POINT('',(-7.03222787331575,4.89,-3.66265124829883));
#496=CARTESIAN_POINT('',(-6.5886459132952,4.89,-3.79380777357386));
#497=CARTESIAN_POINT('',(-6.36654900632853,4.89,-3.85838234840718));
#498=CARTESIAN_POINT('',(-5.92123916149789,4.89,-3.98519699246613));
#499=CARTESIAN_POINT('',(-5.69802491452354,4.89,-4.04743248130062));
#500=CARTESIAN_POINT('',(-5.25076608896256,4.89,-4.16884034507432));
#501=CARTESIAN_POINT('',(-5.02672152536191,4.89,-4.22801277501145));
#502=CARTESIAN_POINT('',(-4.58041494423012,4.89,-4.34183153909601));
#503=CARTESIAN_POINT('',(-4.35816490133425,4.89,-4.39652459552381));
#504=CARTESIAN_POINT('',(-3.91257162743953,4.89,-4.50125107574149));
#505=CARTESIAN_POINT('',(-3.68922844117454,4.89,-4.55128468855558));
#506=CARTESIAN_POINT('',(-3.24137981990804,4.89,-4.64553074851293));
#507=CARTESIAN_POINT('',(-3.01687477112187,4.89,-4.68974501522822));
#508=CARTESIAN_POINT('',(-2.56656126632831,4.89,-4.77100438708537));
#509=CARTESIAN_POINT('',(-2.34075285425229,4.89,-4.80804973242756));
#510=CARTESIAN_POINT('',(-1.91325953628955,4.89,-4.86979826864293));
#511=CARTESIAN_POINT('',(-1.71170849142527,4.89,-4.89541956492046));
#512=CARTESIAN_POINT('',(-1.30775414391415,4.89,-4.93879031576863));
#513=CARTESIAN_POINT('',(-1.10535086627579,4.89,-4.95653999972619));
#514=CARTESIAN_POINT('',(-0.700102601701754,4.89,-4.98331273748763));
#515=CARTESIAN_POINT('',(-0.497258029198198,4.89,-4.99234196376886));
#516=CARTESIAN_POINT('',(-0.0913659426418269,4.89,-5.00121663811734));
#517=CARTESIAN_POINT('',(0.111681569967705,4.89,-5.00106215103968));
#518=CARTESIAN_POINT('',(0.518587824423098,4.89,-4.99155374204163));
#519=CARTESIAN_POINT('',(0.722445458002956,4.89,-4.98215316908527));
#520=CARTESIAN_POINT('',(1.12956194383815,4.89,-4.95458520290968));
#521=CARTESIAN_POINT('',(1.33282078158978,4.89,-4.9364175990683));
#522=CARTESIAN_POINT('',(1.73863931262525,4.89,-4.89216545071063));
#523=CARTESIAN_POINT('',(1.94119825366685,4.89,-4.86607410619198));
#524=CARTESIAN_POINT('',(2.34530277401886,4.89,-4.80703278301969));
#525=CARTESIAN_POINT('',(2.54684834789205,4.89,-4.77408276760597));
#526=CARTESIAN_POINT('',(2.95953215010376,4.89,-4.70050048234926));
#527=CARTESIAN_POINT('',(3.17061386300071,4.89,-4.65955404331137));
#528=CARTESIAN_POINT('',(3.59169320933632,4.89,-4.57239075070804));
#529=CARTESIAN_POINT('',(3.80169075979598,4.89,-4.52617349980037));
#530=CARTESIAN_POINT('',(4.22074597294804,4.89,-4.42944209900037));
#531=CARTESIAN_POINT('',(4.42980337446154,4.89,-4.37892682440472));
#532=CARTESIAN_POINT('',(4.84704782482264,4.89,-4.27441073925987));
#533=CARTESIAN_POINT('',(5.05523484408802,4.89,-4.22040981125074));
#534=CARTESIAN_POINT('',(5.67918655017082,4.89,-4.05405487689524));
#535=CARTESIAN_POINT('',(6.09382208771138,4.89,-3.93747234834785));
#536=CARTESIAN_POINT('',(6.92081542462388,4.89,-3.69682408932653));
#537=CARTESIAN_POINT('',(7.33317357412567,4.89,-3.57275954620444));
#538=CARTESIAN_POINT('',(8.15174363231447,4.89,-3.32083569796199));
#539=CARTESIAN_POINT('',(8.5579731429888,4.89,-3.19303339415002));
#540=CARTESIAN_POINT('',(9.36928967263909,4.89,-2.93379972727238));
#541=CARTESIAN_POINT('',(9.77437663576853,4.89,-2.80236819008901));
#542=CARTESIAN_POINT('',(10.5821449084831,4.89,-2.53736245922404));
#543=CARTESIAN_POINT('',(10.9848295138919,4.89,-2.40379828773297));
#544=CARTESIAN_POINT('',(11.7894926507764,4.89,-2.13466736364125));
#545=CARTESIAN_POINT('',(12.1914712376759,4.89,-1.9991007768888));
#546=CARTESIAN_POINT('',(12.5932087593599,4.89,-1.86283377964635));
#547=B_SPLINE_CURVE_WITH_KNOTS('',3,(#493,#494,#495,#496,#497,#498,#499,#500,#501,#502,#503,
#504,#505,#506,#507,#508,#509,#510,#511,#512,#513,#514,#515,#516,#517,#518,#519,#520,#521,#522,
#523,#524,#525,#526,#527,#528,#529,#530,#531,#532,#533,#534,#535,#536,#537,#538,#539,#540,#541,
#542,#543,#544,#545,#546),.UNSPECIFIED.,.F.,.F.,(4,2,2,2,2,2,2,2,2,2,2,2,2,2,2,2,2,2,2,2,2,2,2,
2,2,2,4),(0.,0.693817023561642,1.38768880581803,2.08285517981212,2.7780090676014,
3.46461177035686,4.15118660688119,4.83754625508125,5.52388290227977,6.1332681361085,
6.74263561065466,7.35157144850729,7.9605029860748,8.57252272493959,9.18455716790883,
9.79711833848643,10.4096827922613,11.054649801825,11.6996654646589,12.3448504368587,
12.9900571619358,14.2820728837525,15.5738841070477,16.8514365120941,18.1290503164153,
19.4018164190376,20.6744776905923),.UNSPECIFIED.);
#548=CARTESIAN_POINT('',(0.,4.89,-5.));
#549=VERTEX_POINT('',#548);
#550=EDGE_CURVE('E337',#549,#490,#547,.T.);
#551=ORIENTED_EDGE('',*,*,#550,.F.);
#552=EDGE_CURVE('E338',#387,#549,#547,.T.);
#553=ORIENTED_EDGE('',*,*,#552,.F.);
#554=ORIENTED_EDGE('',*,*,#388,.T.);
#555=EDGE_CURVE('E282',#59,#379,#480,.F.);
#556=ORIENTED_EDGE('',*,*,#555,.F.);
#557=EDGE_LOOP('',(#484,#492,#551,#553,#554,#556));
#558=FACE_BOUND('',#557,.T.);
#559=ADVANCED_FACE('F320',(#558),#425,.T.);
#560=CARTESIAN_POINT('',(5.64648563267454,0.,-5.));
#561=DIRECTION('',(0.866025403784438,0.5,0.));
#562=DIRECTION('',(-0.5,0.866025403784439,0.));
#563=AXIS2_PLACEMENT_3D('',#560,#561,#562);
#564=PLANE('',#563);
#565=CARTESIAN_POINT('',(5.64660110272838,-0.000199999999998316,-0.275380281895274));
#566=CARTESIAN_POINT('',(5.52967490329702,0.202322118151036,-0.232806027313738));
#567=CARTESIAN_POINT('',(5.41236312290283,0.405512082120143,-0.194077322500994));
#568=CARTESIAN_POINT('',(5.17697676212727,0.813213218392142,-0.125940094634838));
#569=CARTESIAN_POINT('',(5.05890165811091,1.01772529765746,-0.0965388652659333));
#570=CARTESIAN_POINT('',(4.82329906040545,1.42580096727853,-0.0489831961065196));
#571=CARTESIAN_POINT('',(4.7057769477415,1.62935523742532,-0.0307250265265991));
#572=CARTESIAN_POINT('',(4.470457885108,2.03693980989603,-0.00623568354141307));
#573=CARTESIAN_POINT('',(4.35266105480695,2.24096990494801,0.));
#574=CARTESIAN_POINT('',(4.11706739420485,2.64903009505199,0.));
#575=CARTESIAN_POINT('',(3.9992705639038,2.85306019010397,-0.00623568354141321));
#576=CARTESIAN_POINT('',(3.7639515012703,3.26064476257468,-0.0307250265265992));
#577=CARTESIAN_POINT('',(3.64642938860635,3.46419903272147,-0.0489831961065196));
#578=CARTESIAN_POINT('',(3.41082679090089,3.87227470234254,-0.0965388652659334));
#579=CARTESIAN_POINT('',(3.29275168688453,4.07678678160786,-0.125940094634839));
#580=CARTESIAN_POINT('',(3.05736532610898,4.48448791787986,-0.194077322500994));
#581=CARTESIAN_POINT('',(2.94005354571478,4.68767788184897,-0.232806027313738));
#582=CARTESIAN_POINT('',(2.82312734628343,4.8902,-0.275380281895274));
#583=B_SPLINE_CURVE_WITH_KNOTS('',3,(#565,#566,#567,#568,#569,#570,#571,#572,#573,#574,#575,
#576,#577,#578,#579,#580,#581,#582),.UNSPECIFIED.,.F.,.F.,(4,2,2,2,2,2,2,2,4),(0.,
0.713162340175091,1.42688097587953,2.13385008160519,2.84055392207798,3.54725776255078,
4.25422686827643,4.96794550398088,5.68110784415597),.UNSPECIFIED.);
#584=EDGE_CURVE('E171',#140,#55,#583,.T.);
#585=ORIENTED_EDGE('',*,*,#584,.F.);
#586=ORIENTED_EDGE('',*,*,#141,.F.);
#587=CARTESIAN_POINT('',(2.82312734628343,4.8902,-4.72461971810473));
#588=CARTESIAN_POINT('',(2.94005354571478,4.68767788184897,-4.76719397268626));
#589=CARTESIAN_POINT('',(3.05736532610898,4.48448791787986,-4.80592267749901));
#590=CARTESIAN_POINT('',(3.29275168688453,4.07678678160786,-4.87405990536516));
#591=CARTESIAN_POINT('',(3.41082679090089,3.87227470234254,-4.90346113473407));
#592=CARTESIAN_POINT('',(3.64642938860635,3.46419903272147,-4.95101680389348));
#593=CARTESIAN_POINT('',(3.7639515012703,3.26064476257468,-4.9692749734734));
#594=CARTESIAN_POINT('',(3.9992705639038,2.85306019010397,-4.99376431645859));
#595=CARTESIAN_POINT('',(4.11706739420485,2.64903009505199,-5.));
#596=CARTESIAN_POINT('',(4.35266105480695,2.24096990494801,-5.));
#597=CARTESIAN_POINT('',(4.470457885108,2.03693980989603,-4.99376431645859));
#598=CARTESIAN_POINT('',(4.7057769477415,1.62935523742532,-4.9692749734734));
#599=CARTESIAN_POINT('',(4.82329906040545,1.42580096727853,-4.95101680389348));
#600=CARTESIAN_POINT('',(5.05890165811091,1.01772529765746,-4.90346113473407));
#601=CARTESIAN_POINT('',(5.17697676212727,0.813213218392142,-4.87405990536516));
#602=CARTESIAN_POINT('',(5.41236312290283,0.405512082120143,-4.80592267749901));
#603=CARTESIAN_POINT('',(5.52967490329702,0.202322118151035,-4.76719397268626));
#604=CARTESIAN_POINT('',(5.64660110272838,-0.000199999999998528,-4.72461971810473));
#605=B_SPLINE_CURVE_WITH_KNOTS('',3,(#587,#588,#589,#590,#591,#592,#593,#594,#595,#596,#597,
#598,#599,#600,#601,#602,#603,#604),.UNSPECIFIED.,.F.,.F.,(4,2,2,2,2,2,2,2,4),(0.,
0.713162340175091,1.42688097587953,2.13385008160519,2.84055392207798,3.54725776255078,
4.25422686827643,4.96794550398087,5.68110784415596),.UNSPECIFIED.);
#606=CARTESIAN_POINT('',(4.2348642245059,2.445,-5.));
#607=VERTEX_POINT('',#606);
#608=EDGE_CURVE('E343',#607,#132,#605,.T.);
#609=ORIENTED_EDGE('',*,*,#608,.F.);
#610=EDGE_CURVE('E335',#490,#607,#605,.T.);
#611=ORIENTED_EDGE('',*,*,#610,.F.);
#612=ORIENTED_EDGE('',*,*,#491,.T.);
#613=EDGE_CURVE('E163',#55,#482,#583,.T.);
#614=ORIENTED_EDGE('',*,*,#613,.F.);
#615=EDGE_LOOP('',(#585,#586,#609,#611,#612,#614));
#616=FACE_BOUND('',#615,.T.);
#617=ADVANCED_FACE('F179',(#616),#564,.T.);
#618=CARTESIAN_POINT('',(2.82324281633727,-4.89,-5.));
#619=DIRECTION('',(0.,0.,-1.));
#620=DIRECTION('',(-1.,0.,0.));
#621=AXIS2_PLACEMENT_3D('',#618,#619,#620);
#622=PLANE('',#621);
#623=CARTESIAN_POINT('',(0.,0.,-5.));
#624=DIRECTION('',(0.,0.,-1.));
#625=DIRECTION('',(-1.,0.,0.));
#626=AXIS2_PLACEMENT_3D('',#623,#624,#625);
#627=CIRCLE('',#626,2.87527767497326);
#628=CARTESIAN_POINT('',(-2.87527767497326,0.,-5.));
#629=VERTEX_POINT('',#628);
#630=EDGE_CURVE('E55',#629,#629,#627,.F.);
#631=ORIENTED_EDGE('',*,*,#630,.T.);
#632=EDGE_LOOP('',(#631));
#633=FACE_BOUND('',#632,.T.);
#634=CARTESIAN_POINT('',(0.,0.,-5.));
#635=DIRECTION('',(0.,0.,-1.));
#636=DIRECTION('',(-1.,0.,0.));
#637=AXIS2_PLACEMENT_3D('',#634,#635,#636);
#638=CIRCLE('',#637,4.89);
#639=EDGE_CURVE('E292',#343,#276,#638,.F.);
#640=ORIENTED_EDGE('',*,*,#639,.F.);
#641=EDGE_CURVE('E287',#410,#343,#638,.F.);
#642=ORIENTED_EDGE('',*,*,#641,.F.);
#643=CARTESIAN_POINT('',(0.,0.,-5.));
#644=DIRECTION('',(0.,0.,-1.));
#645=DIRECTION('',(-1.,0.,0.));
#646=AXIS2_PLACEMENT_3D('',#643,#644,#645);
#647=CIRCLE('',#646,4.89);
#648=EDGE_CURVE('E378',#410,#549,#647,.T.);
#649=ORIENTED_EDGE('',*,*,#648,.T.);
#650=EDGE_CURVE('E290',#607,#549,#638,.F.);
#651=ORIENTED_EDGE('',*,*,#650,.F.);
#652=EDGE_CURVE('E425',#128,#607,#638,.F.);
#653=ORIENTED_EDGE('',*,*,#652,.F.);
#654=EDGE_CURVE('E608',#276,#128,#638,.F.);
#655=ORIENTED_EDGE('',*,*,#654,.F.);
#656=EDGE_LOOP('',(#640,#642,#649,#651,#653,#655));
#657=FACE_BOUND('',#656,.T.);
#658=ADVANCED_FACE('F431',(#633,#657),#622,.T.);
#659=CARTESIAN_POINT('',(0.,0.,0.));
#660=DIRECTION('',(0.,0.,1.));
#661=DIRECTION('',(1.,0.,0.));
#662=AXIS2_PLACEMENT_3D('',#659,#660,#661);
#663=CIRCLE('',#662,3.25);
#664=CARTESIAN_POINT('',(3.25,0.,0.));
#665=VERTEX_POINT('',#664);
#666=EDGE_CURVE('E149',#665,#665,#663,.T.);
#667=ORIENTED_EDGE('',*,*,#666,.T.);
#668=EDGE_LOOP('',(#667));
#669=FACE_BOUND('',#668,.T.);
#670=CARTESIAN_POINT('',(0.,0.,0.));
#671=DIRECTION('',(0.,0.,1.));
#672=DIRECTION('',(1.,0.,0.));
#673=AXIS2_PLACEMENT_3D('',#670,#671,#672);
#674=CIRCLE('',#673,2.5);
#675=CARTESIAN_POINT('',(2.5,0.,0.));
#676=VERTEX_POINT('',#675);
#677=EDGE_CURVE('E262',#676,#676,#674,.T.);
#678=ORIENTED_EDGE('',*,*,#677,.F.);
#679=EDGE_LOOP('',(#678));
#680=FACE_BOUND('',#679,.T.);
#681=ADVANCED_FACE('F235',(#669,#680),#23,.F.);
#682=CARTESIAN_POINT('',(0.,0.,-5.));
#683=DIRECTION('',(0.,0.,1.));
#684=DIRECTION('',(1.,0.,0.));
#685=AXIS2_PLACEMENT_3D('',#682,#683,#684);
#686=CYLINDRICAL_SURFACE('',#685,2.5);
#687=CARTESIAN_POINT('',(0.,0.,-4.34999999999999));
#688=DIRECTION('',(0.,0.,-1.));
#689=DIRECTION('',(-1.,0.,0.));
#690=AXIS2_PLACEMENT_3D('',#687,#688,#689);
#691=CIRCLE('',#690,2.5);
#692=CARTESIAN_POINT('',(-2.5,0.,-4.34999999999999));
#693=VERTEX_POINT('',#692);
#694=EDGE_CURVE('E12',#693,#693,#691,.T.);
#695=ORIENTED_EDGE('',*,*,#694,.T.);
#696=EDGE_LOOP('',(#695));
#697=FACE_BOUND('',#696,.T.);
#698=ORIENTED_EDGE('',*,*,#677,.T.);
#699=EDGE_LOOP('',(#698));
#700=FACE_BOUND('',#699,.T.);
#701=ADVANCED_FACE('F403',(#697,#700),#686,.F.);
#702=CARTESIAN_POINT('',(0.,0.,-4.72466174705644));
#703=DIRECTION('',(0.,0.,1.));
#704=DIRECTION('',(1.,0.,0.));
#705=AXIS2_PLACEMENT_3D('',#702,#703,#704);
#706=CONICAL_SURFACE('',#705,5.64648563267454,1.22173047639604);
#707=ORIENTED_EDGE('',*,*,#344,.T.);
#708=ORIENTED_EDGE('',*,*,#413,.T.);
#709=ORIENTED_EDGE('',*,*,#641,.T.);
#710=EDGE_LOOP('',(#707,#708,#709));
#711=FACE_BOUND('',#710,.T.);
#712=ADVANCED_FACE('F395',(#711),#706,.T.);
#713=ORIENTED_EDGE('',*,*,#411,.T.);
#714=ORIENTED_EDGE('',*,*,#552,.T.);
#715=ORIENTED_EDGE('',*,*,#648,.F.);
#716=EDGE_LOOP('',(#713,#714,#715));
#717=FACE_BOUND('',#716,.T.);
#718=ADVANCED_FACE('F402',(#717),#706,.T.);
#719=ORIENTED_EDGE('',*,*,#550,.T.);
#720=ORIENTED_EDGE('',*,*,#610,.T.);
#721=ORIENTED_EDGE('',*,*,#650,.T.);
#722=EDGE_LOOP('',(#719,#720,#721));
#723=FACE_BOUND('',#722,.T.);
#724=ADVANCED_FACE('F192',(#723),#706,.T.);
#725=ORIENTED_EDGE('',*,*,#133,.T.);
#726=ORIENTED_EDGE('',*,*,#652,.T.);
#727=ORIENTED_EDGE('',*,*,#608,.T.);
#728=EDGE_LOOP('',(#725,#726,#727));
#729=FACE_BOUND('',#728,.T.);
#730=ADVANCED_FACE('F399',(#729),#706,.T.);
#731=ORIENTED_EDGE('',*,*,#129,.T.);
#732=ORIENTED_EDGE('',*,*,#279,.T.);
#733=ORIENTED_EDGE('',*,*,#654,.T.);
#734=EDGE_LOOP('',(#731,#732,#733));
#735=FACE_BOUND('',#734,.T.);
#736=ADVANCED_FACE('F393',(#735),#706,.T.);
#737=ORIENTED_EDGE('',*,*,#277,.T.);
#738=ORIENTED_EDGE('',*,*,#346,.T.);
#739=ORIENTED_EDGE('',*,*,#639,.T.);
#740=EDGE_LOOP('',(#737,#738,#739));
#741=FACE_BOUND('',#740,.T.);
#742=ADVANCED_FACE('F389',(#741),#706,.T.);
#743=CARTESIAN_POINT('',(0.,0.,0.));
#744=DIRECTION('',(0.,0.,-1.));
#745=DIRECTION('',(-1.,0.,0.));
#746=AXIS2_PLACEMENT_3D('',#743,#744,#745);
#747=CONICAL_SURFACE('',#746,4.89,1.22173047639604);
#748=ORIENTED_EDGE('',*,*,#313,.T.);
#749=ORIENTED_EDGE('',*,*,#44,.F.);
#750=ORIENTED_EDGE('',*,*,#416,.T.);
#751=EDGE_LOOP('',(#748,#749,#750));
#752=FACE_BOUND('',#751,.T.);
#753=ADVANCED_FACE('F189',(#752),#747,.T.);
#754=ORIENTED_EDGE('',*,*,#380,.T.);
#755=ORIENTED_EDGE('',*,*,#67,.T.);
#756=ORIENTED_EDGE('',*,*,#555,.T.);
#757=EDGE_LOOP('',(#754,#755,#756));
#758=FACE_BOUND('',#757,.T.);
#759=ADVANCED_FACE('F187',(#758),#747,.T.);
#760=ORIENTED_EDGE('',*,*,#483,.T.);
#761=ORIENTED_EDGE('',*,*,#60,.F.);
#762=ORIENTED_EDGE('',*,*,#613,.T.);
#763=EDGE_LOOP('',(#760,#761,#762));
#764=FACE_BOUND('',#763,.T.);
#765=ADVANCED_FACE('F181',(#764),#747,.T.);
#766=ORIENTED_EDGE('',*,*,#143,.T.);
#767=ORIENTED_EDGE('',*,*,#584,.T.);
#768=ORIENTED_EDGE('',*,*,#56,.F.);
#769=EDGE_LOOP('',(#766,#767,#768));
#770=FACE_BOUND('',#769,.T.);
#771=ADVANCED_FACE('F186',(#770),#747,.T.);
#772=ORIENTED_EDGE('',*,*,#282,.T.);
#773=ORIENTED_EDGE('',*,*,#98,.T.);
#774=ORIENTED_EDGE('',*,*,#52,.F.);
#775=EDGE_LOOP('',(#772,#773,#774));
#776=FACE_BOUND('',#775,.T.);
#777=ADVANCED_FACE('F379',(#776),#747,.T.);
#778=ORIENTED_EDGE('',*,*,#349,.T.);
#779=ORIENTED_EDGE('',*,*,#210,.T.);
#780=ORIENTED_EDGE('',*,*,#48,.F.);
#781=EDGE_LOOP('',(#778,#779,#780));
#782=FACE_BOUND('',#781,.T.);
#783=ADVANCED_FACE('F143',(#782),#747,.T.);
#784=CARTESIAN_POINT('',(0.,0.,2.));
#785=DIRECTION('',(0.,0.,-1.));
#786=DIRECTION('',(-1.,0.,0.));
#787=AXIS2_PLACEMENT_3D('',#784,#785,#786);
#788=CONICAL_SURFACE('',#787,3.25,0.825376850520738);
#789=CARTESIAN_POINT('',(0.,0.,5.));
#790=VERTEX_POINT('',#789);
#791=VERTEX_LOOP('',#790);
#792=FACE_BOUND('',#791,.T.);
#793=CARTESIAN_POINT('',(0.,0.,2.));
#794=DIRECTION('',(0.,0.,1.));
#795=DIRECTION('',(1.,0.,0.));
#796=AXIS2_PLACEMENT_3D('',#793,#794,#795);
#797=CIRCLE('',#796,3.25);
#798=CARTESIAN_POINT('',(3.25,0.,2.));
#799=VERTEX_POINT('',#798);
#800=EDGE_CURVE('E147',#799,#799,#797,.T.);
#801=ORIENTED_EDGE('',*,*,#800,.F.);
#802=EDGE_LOOP('',(#801));
#803=FACE_BOUND('',#802,.T.);
#804=ADVANCED_FACE('F139',(#792,#803),#788,.F.);
#805=CARTESIAN_POINT('',(0.,0.,6.));
#806=DIRECTION('',(0.,0.,1.));
#807=DIRECTION('',(1.,0.,0.));
#808=AXIS2_PLACEMENT_3D('',#805,#806,#807);
#809=CYLINDRICAL_SURFACE('',#808,3.25);
#810=ORIENTED_EDGE('',*,*,#800,.T.);
#811=EDGE_LOOP('',(#810));
#812=FACE_BOUND('',#811,.T.);
#813=ORIENTED_EDGE('',*,*,#666,.F.);
#814=EDGE_LOOP('',(#813));
#815=FACE_BOUND('',#814,.T.);
#816=ADVANCED_FACE('F142',(#812,#815),#809,.F.);
#817=CARTESIAN_POINT('',(0.,0.,1.4));
#818=DIRECTION('',(0.,0.,1.));
#819=DIRECTION('',(1.,0.,0.));
#820=AXIS2_PLACEMENT_3D('',#817,#818,#819);
#821=SPHERICAL_SURFACE('',#820,4.6);
#822=CARTESIAN_POINT('',(0.,0.,1.4));
#823=DIRECTION('',(0.,0.,1.));
#824=DIRECTION('',(1.,0.,0.));
#825=AXIS2_PLACEMENT_3D('',#822,#823,#824);
#826=CIRCLE('',#825,4.6);
#827=CARTESIAN_POINT('',(4.6,0.,1.4));
#828=VERTEX_POINT('',#827);
#829=EDGE_CURVE('E157',#828,#828,#826,.T.);
#830=ORIENTED_EDGE('',*,*,#829,.T.);
#831=EDGE_LOOP('',(#830));
#832=FACE_BOUND('',#831,.T.);
#833=ADVANCED_FACE('F190',(#832),#821,.T.);
#834=CARTESIAN_POINT('',(0.,0.,6.));
#835=DIRECTION('',(0.,0.,1.));
#836=DIRECTION('',(1.,0.,0.));
#837=AXIS2_PLACEMENT_3D('',#834,#835,#836);
#838=CYLINDRICAL_SURFACE('',#837,4.6);
#839=ORIENTED_EDGE('',*,*,#31,.T.);
#840=EDGE_LOOP('',(#839));
#841=FACE_BOUND('',#840,.T.);
#842=ORIENTED_EDGE('',*,*,#829,.F.);
#843=EDGE_LOOP('',(#842));
#844=FACE_BOUND('',#843,.T.);
#845=ADVANCED_FACE('F443',(#841,#844),#838,.T.);
#846=CARTESIAN_POINT('',(0.,0.,-5.));
#847=DIRECTION('',(0.,0.,-1.));
#848=DIRECTION('',(-1.,0.,0.));
#849=AXIS2_PLACEMENT_3D('',#846,#847,#848);
#850=CONICAL_SURFACE('',#849,2.87527767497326,0.523598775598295);
#851=ORIENTED_EDGE('',*,*,#694,.F.);
#852=EDGE_LOOP('',(#851));
#853=FACE_BOUND('',#852,.T.);
#854=ORIENTED_EDGE('',*,*,#630,.F.);
#855=EDGE_LOOP('',(#854));
#856=FACE_BOUND('',#855,.T.);
#857=ADVANCED_FACE('F49',(#853,#856),#850,.F.);
#858=CLOSED_SHELL('',(#71,#147,#286,#353,#420,#559,#617,#658,#681,#701,#712,#718,#724,#730,#736,
#742,#753,#759,#765,#771,#777,#783,#804,#816,#833,#845,#857));
#859=MANIFOLD_SOLID_BREP('B2',#858);
#860=ADVANCED_BREP_SHAPE_REPRESENTATION('',(#18,#859),#14);
#861=SHAPE_DEFINITION_REPRESENTATION(#9,#860);
ENDSEC;
END-ISO-10303-21;
